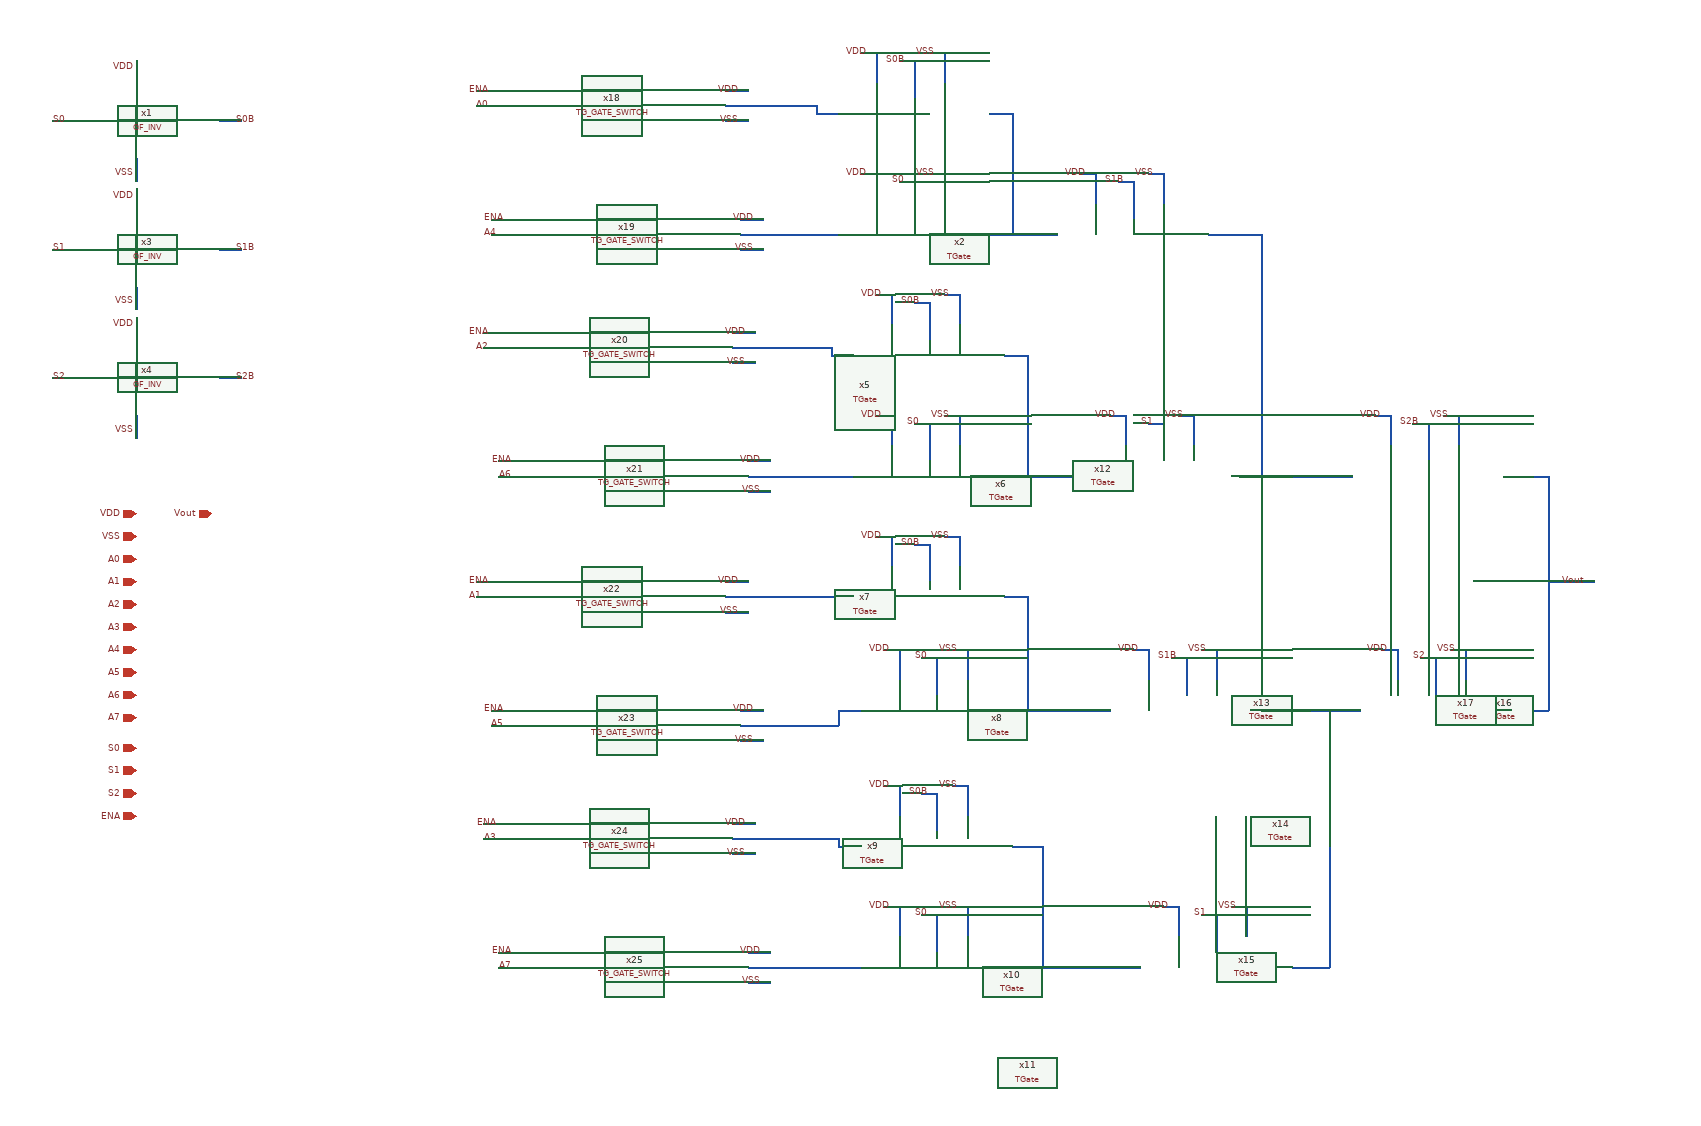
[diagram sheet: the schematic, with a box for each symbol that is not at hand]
v {xschem version=3.4.3 file_version=1.2
}
G {}
K {}
V {}
S {}
E {}
N -660 -160 -660 -130 {
lab=VDD}
N -770 -80 -730 -80 {
lab=S0}
N -660 -30 -660 0 {
lab=VSS}
N -550 -80 -520 -80 {
lab=S0B}
N -660 10 -660 40 {
lab=VDD}
N -770 90 -730 90 {
lab=S1}
N -660 140 -660 170 {
lab=VSS}
N -550 90 -520 90 {
lab=S1B}
N -660 180 -660 210 {
lab=VDD}
N -770 260 -730 260 {
lab=S2}
N -660 310 -660 340 {
lab=VSS}
N -550 260 -520 260 {
lab=S2B}
N 320 -170 320 -130 {
lab=VDD}
N 300 -170 320 -170 {
lab=VDD}
N 370 -160 370 -110 {
lab=S0B}
N 350 -160 370 -160 {
lab=S0B}
N 410 -170 410 -130 {
lab=VSS}
N 390 -170 410 -170 {
lab=VSS}
N 240 -90 270 -90 {
lab=#net1}
N 470 -90 500 -90 {
lab=#net2}
N 320 -10 320 30 {
lab=VDD}
N 300 -10 320 -10 {
lab=VDD}
N 370 0 370 50 {
lab=S0}
N 350 0 370 0 {
lab=S0}
N 410 -10 410 30 {
lab=VSS}
N 390 -10 410 -10 {
lab=VSS}
N 240 70 270 70 {
lab=#net3}
N 340 150 340 190 {
lab=VDD}
N 320 150 340 150 {
lab=VDD}
N 390 160 390 210 {
lab=S0B}
N 370 160 390 160 {
lab=S0B}
N 430 150 430 190 {
lab=VSS}
N 410 150 430 150 {
lab=VSS}
N 260 230 290 230 {
lab=#net4}
N 490 230 520 230 {
lab=#net5}
N 340 310 340 350 {
lab=VDD}
N 320 310 340 310 {
lab=VDD}
N 390 320 390 370 {
lab=S0}
N 370 320 390 320 {
lab=S0}
N 430 310 430 350 {
lab=VSS}
N 410 310 430 310 {
lab=VSS}
N 260 390 290 390 {
lab=#net6}
N 340 470 340 510 {
lab=VDD}
N 320 470 340 470 {
lab=VDD}
N 390 480 390 530 {
lab=S0B}
N 370 480 390 480 {
lab=S0B}
N 430 470 430 510 {
lab=VSS}
N 410 470 430 470 {
lab=VSS}
N 260 550 290 550 {
lab=#net7}
N 490 550 520 550 {
lab=#net8}
N 350 620 350 660 {
lab=VDD}
N 330 620 350 620 {
lab=VDD}
N 400 630 400 680 {
lab=S0}
N 380 630 400 630 {
lab=S0}
N 440 620 440 660 {
lab=VSS}
N 420 620 440 620 {
lab=VSS}
N 270 700 300 700 {
lab=#net9}
N 350 800 350 840 {
lab=VDD}
N 330 800 350 800 {
lab=VDD}
N 400 810 400 860 {
lab=S0B}
N 380 810 400 810 {
lab=S0B}
N 440 800 440 840 {
lab=VSS}
N 420 800 440 800 {
lab=VSS}
N 270 880 300 880 {
lab=#net10}
N 500 880 530 880 {
lab=#net11}
N 350 960 350 1000 {
lab=VDD}
N 330 960 350 960 {
lab=VDD}
N 400 970 400 1020 {
lab=S0}
N 380 970 400 970 {
lab=S0}
N 440 960 440 1000 {
lab=VSS}
N 420 960 440 960 {
lab=VSS}
N 270 1040 300 1040 {
lab=A7}
N 610 -10 610 30 {
lab=VDD}
N 590 -10 610 -10 {
lab=VDD}
N 660 0 660 50 {
lab=S1B}
N 640 0 660 0 {
lab=S1B}
N 700 -10 700 30 {
lab=VSS}
N 680 -10 700 -10 {
lab=VSS}
N 650 310 650 350 {
lab=VDD}
N 630 310 650 310 {
lab=VDD}
N 700 320 700 370 {
lab=S1}
N 680 320 700 320 {
lab=S1}
N 740 310 740 350 {
lab=VSS}
N 720 310 740 310 {
lab=VSS}
N 680 620 680 660 {
lab=VDD}
N 660 620 680 620 {
lab=VDD}
N 730 630 730 680 {
lab=S1B}
N 710 630 730 630 {
lab=S1B}
N 770 620 770 660 {
lab=VSS}
N 750 620 770 620 {
lab=VSS}
N 720 960 720 1000 {
lab=VDD}
N 700 960 720 960 {
lab=VDD}
N 770 970 770 1020 {
lab=S1}
N 750 970 770 970 {
lab=S1}
N 810 960 810 1000 {
lab=VSS}
N 790 960 810 960 {
lab=VSS}
N 870 1040 900 1040 {
lab=#net12}
N 1000 310 1000 350 {
lab=VDD}
N 980 310 1000 310 {
lab=VDD}
N 1050 320 1050 370 {
lab=S2B}
N 1030 320 1050 320 {
lab=S2B}
N 1090 310 1090 350 {
lab=VSS}
N 1070 310 1090 310 {
lab=VSS}
N 1010 620 1010 660 {
lab=VDD}
N 990 620 1010 620 {
lab=VDD}
N 1060 630 1060 680 {
lab=S2}
N 1040 630 1060 630 {
lab=S2}
N 1100 620 1100 660 {
lab=VSS}
N 1080 620 1100 620 {
lab=VSS}
N 470 70 560 70 {
lab=#net2}
N 500 -90 500 70 {
lab=#net2}
N 490 390 600 390 {
lab=#net5}
N 520 230 520 390 {
lab=#net5}
N 500 700 630 700 {
lab=#net8}
N 520 550 520 700 {
lab=#net8}
N 500 1040 670 1040 {
lab=#net11}
N 530 880 540 880 {
lab=#net11}
N 540 880 540 1040 {
lab=#net11}
N 800 390 950 390 {
lab=#net13}
N 830 700 960 700 {
lab=#net12}
N 760 70 830 70 {
lab=#net13}
N 830 70 830 390 {
lab=#net13}
N 900 1040 920 1040 {
lab=#net12}
N 920 700 920 1040 {
lab=#net12}
N 1160 700 1210 700 {
lab=Vout}
N 1210 390 1210 700 {
lab=Vout}
N 1150 390 1210 390 {
lab=Vout}
N 1210 530 1270 530 {
lab=Vout}
N 120 -120 150 -120 {
lab=VDD}
N 120 -100 150 -100 {
lab=#net1}
N 120 -80 150 -80 {
lab=VSS}
N -210 -120 -180 -120 {
lab=ENA}
N -190 -100 -180 -100 {
lab=A0}
N -210 -100 -190 -100 {
lab=A0}
N 140 50 170 50 {
lab=VDD}
N 140 70 170 70 {
lab=#net3}
N 140 90 170 90 {
lab=VSS}
N -190 50 -160 50 {
lab=ENA}
N -170 70 -160 70 {
lab=A4}
N -190 70 -170 70 {
lab=A4}
N 130 200 160 200 {
lab=VDD}
N 130 220 160 220 {
lab=#net4}
N 130 240 160 240 {
lab=VSS}
N -200 200 -170 200 {
lab=ENA}
N -180 220 -170 220 {
lab=A2}
N -200 220 -180 220 {
lab=A2}
N 150 370 180 370 {
lab=VDD}
N 150 390 180 390 {
lab=#net6}
N 150 410 180 410 {
lab=VSS}
N -180 370 -150 370 {
lab=ENA}
N -160 390 -150 390 {
lab=A6}
N -180 390 -160 390 {
lab=A6}
N 120 530 150 530 {
lab=VDD}
N 120 550 150 550 {
lab=#net7}
N 120 570 150 570 {
lab=VSS}
N -210 530 -180 530 {
lab=ENA}
N -190 550 -180 550 {
lab=A1}
N -210 550 -190 550 {
lab=A1}
N 140 700 170 700 {
lab=VDD}
N 140 720 170 720 {
lab=#net9}
N 140 740 170 740 {
lab=VSS}
N -190 700 -160 700 {
lab=ENA}
N -170 720 -160 720 {
lab=A5}
N -190 720 -170 720 {
lab=A5}
N 130 850 160 850 {
lab=VDD}
N 130 870 160 870 {
lab=#net14}
N 130 890 160 890 {
lab=VSS}
N -200 850 -170 850 {
lab=ENA}
N -180 870 -170 870 {
lab=A3}
N -200 870 -180 870 {
lab=A3}
N 150 1020 180 1020 {
lab=VDD}
N 150 1040 180 1040 {
lab=#net15}
N 150 1060 180 1060 {
lab=VSS}
N -180 1020 -150 1020 {
lab=ENA}
N -160 1040 -150 1040 {
lab=#net16}
N -180 1040 -160 1040 {
lab=#net16}
N 150 -100 240 -100 {
lab=#net1}
N 240 -100 240 -90 {
lab=#net1}
N 170 70 240 70 {
lab=#net3}
N 160 220 260 220 {
lab=#net4}
N 260 220 260 230 {
lab=#net4}
N 180 390 260 390 {
lab=#net6}
N 150 550 200 550 {
lab=#net7}
N 200 550 260 550 {
lab=#net7}
N 170 720 270 720 {
lab=#net9}
N 270 700 270 720 {
lab=#net9}
N 160 870 270 870 {}
N 270 870 270 880 {}
N 180 1040 270 1040 {}
C {GF_INV.sym} -660 -80 0 0 {name=x1}
C {devices/lab_wire.sym} -660 -150 0 0 {name=p4 sig_type=std_logic lab=VDD}
C {devices/lab_wire.sym} -750 -80 0 0 {name=p5 sig_type=std_logic lab=S0}
C {devices/lab_wire.sym} -660 -10 0 0 {name=p6 sig_type=std_logic lab=VSS}
C {devices/lab_wire.sym} -530 -80 0 1 {name=p7 sig_type=std_logic lab=S0B}
C {GF_INV.sym} -660 90 0 0 {name=x3}
C {devices/lab_wire.sym} -660 20 0 0 {name=p8 sig_type=std_logic lab=VDD}
C {devices/lab_wire.sym} -750 90 0 0 {name=p9 sig_type=std_logic lab=S1}
C {devices/lab_wire.sym} -660 160 0 0 {name=p10 sig_type=std_logic lab=VSS}
C {devices/lab_wire.sym} -530 90 0 1 {name=p11 sig_type=std_logic lab=S1B}
C {GF_INV.sym} -660 260 0 0 {name=x4}
C {devices/lab_wire.sym} -660 190 0 0 {name=p12 sig_type=std_logic lab=VDD}
C {devices/lab_wire.sym} -750 260 0 0 {name=p13 sig_type=std_logic lab=S2}
C {devices/lab_wire.sym} -660 330 0 0 {name=p14 sig_type=std_logic lab=VSS}
C {devices/lab_wire.sym} -530 260 0 1 {name=p15 sig_type=std_logic lab=S2B}
C {TGate.sym} 490 50 0 0 {name=x2}
C {devices/lab_wire.sym} 310 -170 0 0 {name=p1 sig_type=std_logic lab=VDD}
C {devices/lab_wire.sym} 400 -170 0 0 {name=p2 sig_type=std_logic lab=VSS}
C {TGate.sym} 490 210 0 0 {name=x5}
C {devices/lab_wire.sym} 310 -10 0 0 {name=p3 sig_type=std_logic lab=VDD}
C {devices/lab_wire.sym} 400 -10 0 0 {name=p16 sig_type=std_logic lab=VSS}
C {TGate.sym} 510 370 0 0 {name=x6}
C {devices/lab_wire.sym} 330 150 0 0 {name=p17 sig_type=std_logic lab=VDD}
C {devices/lab_wire.sym} 420 150 0 0 {name=p18 sig_type=std_logic lab=VSS}
C {TGate.sym} 510 530 0 0 {name=x7}
C {devices/lab_wire.sym} 330 310 0 0 {name=p19 sig_type=std_logic lab=VDD}
C {devices/lab_wire.sym} 420 310 0 0 {name=p20 sig_type=std_logic lab=VSS}
C {TGate.sym} 510 690 0 0 {name=x8}
C {devices/lab_wire.sym} 330 470 0 0 {name=p21 sig_type=std_logic lab=VDD}
C {devices/lab_wire.sym} 420 470 0 0 {name=p22 sig_type=std_logic lab=VSS}
C {TGate.sym} 520 840 0 0 {name=x9}
C {devices/lab_wire.sym} 340 620 0 0 {name=p23 sig_type=std_logic lab=VDD}
C {devices/lab_wire.sym} 430 620 0 0 {name=p24 sig_type=std_logic lab=VSS}
C {TGate.sym} 520 1020 0 0 {name=x10}
C {devices/lab_wire.sym} 340 800 0 0 {name=p25 sig_type=std_logic lab=VDD}
C {devices/lab_wire.sym} 430 800 0 0 {name=p26 sig_type=std_logic lab=VSS}
C {TGate.sym} 520 1180 0 0 {name=x11}
C {devices/lab_wire.sym} 340 960 0 0 {name=p27 sig_type=std_logic lab=VDD}
C {devices/lab_wire.sym} 430 960 0 0 {name=p28 sig_type=std_logic lab=VSS}
C {TGate.sym} 780 210 0 0 {name=x12}
C {devices/lab_wire.sym} 600 -10 0 0 {name=p29 sig_type=std_logic lab=VDD}
C {devices/lab_wire.sym} 690 -10 0 0 {name=p30 sig_type=std_logic lab=VSS}
C {TGate.sym} 820 530 0 0 {name=x13}
C {devices/lab_wire.sym} 640 310 0 0 {name=p31 sig_type=std_logic lab=VDD}
C {devices/lab_wire.sym} 730 310 0 0 {name=p32 sig_type=std_logic lab=VSS}
C {TGate.sym} 850 840 0 0 {name=x14}
C {devices/lab_wire.sym} 670 620 0 0 {name=p33 sig_type=std_logic lab=VDD}
C {devices/lab_wire.sym} 760 620 0 0 {name=p34 sig_type=std_logic lab=VSS}
C {TGate.sym} 890 1180 0 0 {name=x15}
C {devices/lab_wire.sym} 710 960 0 0 {name=p35 sig_type=std_logic lab=VDD}
C {devices/lab_wire.sym} 800 960 0 0 {name=p36 sig_type=std_logic lab=VSS}
C {TGate.sym} 1170 530 0 0 {name=x16}
C {devices/lab_wire.sym} 990 310 0 0 {name=p37 sig_type=std_logic lab=VDD}
C {devices/lab_wire.sym} 1080 310 0 0 {name=p38 sig_type=std_logic lab=VSS}
C {TGate.sym} 1180 840 0 0 {name=x17}
C {devices/lab_wire.sym} 1000 620 0 0 {name=p39 sig_type=std_logic lab=VDD}
C {devices/lab_wire.sym} 1090 620 0 0 {name=p40 sig_type=std_logic lab=VSS}
C {devices/lab_wire.sym} 390 970 0 0 {name=p41 sig_type=std_logic lab=S0}
C {devices/lab_wire.sym} 390 810 0 0 {name=p42 sig_type=std_logic lab=S0B}
C {devices/lab_wire.sym} 390 630 0 0 {name=p43 sig_type=std_logic lab=S0}
C {devices/lab_wire.sym} 380 480 0 0 {name=p44 sig_type=std_logic lab=S0B}
C {devices/lab_wire.sym} 380 320 0 0 {name=p45 sig_type=std_logic lab=S0}
C {devices/lab_wire.sym} 380 160 0 0 {name=p46 sig_type=std_logic lab=S0B}
C {devices/lab_wire.sym} 360 0 0 0 {name=p47 sig_type=std_logic lab=S0}
C {devices/lab_wire.sym} 360 -160 0 0 {name=p48 sig_type=std_logic lab=S0B}
C {devices/lab_wire.sym} 650 0 0 0 {name=p49 sig_type=std_logic lab=S1B}
C {devices/lab_wire.sym} 690 320 0 0 {name=p50 sig_type=std_logic lab=S1}
C {devices/lab_wire.sym} 720 630 0 0 {name=p51 sig_type=std_logic lab=S1B}
C {devices/lab_wire.sym} 760 970 0 0 {name=p52 sig_type=std_logic lab=S1}
C {devices/lab_wire.sym} 1050 630 0 0 {name=p53 sig_type=std_logic lab=S2}
C {devices/lab_wire.sym} 1040 320 0 0 {name=p54 sig_type=std_logic lab=S2B}
C {devices/iopin.sym} -660 440 2 0 {name=p55 lab=VDD}
C {devices/iopin.sym} -660 470 2 0 {name=p56 lab=VSS}
C {devices/iopin.sym} -660 500 2 0 {name=p57 lab=A0}
C {devices/iopin.sym} -660 530 2 0 {name=p58 lab=A1}
C {devices/iopin.sym} -660 560 2 0 {name=p59 lab=A2}
C {devices/iopin.sym} -660 590 2 0 {name=p60 lab=A3}
C {devices/iopin.sym} -660 620 2 0 {name=p61 lab=A4}
C {devices/iopin.sym} -660 650 2 0 {name=p62 lab=A5}
C {devices/iopin.sym} -660 680 2 0 {name=p63 lab=A6}
C {devices/iopin.sym} -660 710 2 0 {name=p64 lab=A7}
C {devices/ipin.sym} -660 750 0 0 {name=p65 lab=S0}
C {devices/ipin.sym} -660 780 0 0 {name=p66 lab=S1}
C {devices/ipin.sym} -660 810 0 0 {name=p67 lab=S2}
C {devices/iopin.sym} -560 440 2 0 {name=p68 lab=Vout}
C {devices/lab_wire.sym} -190 -100 0 0 {name=p69 sig_type=std_logic lab=A0}
C {devices/lab_wire.sym} -180 70 0 0 {name=p70 sig_type=std_logic lab=A4}
C {devices/lab_wire.sym} -190 220 0 0 {name=p71 sig_type=std_logic lab=A2}
C {devices/lab_wire.sym} -160 390 0 0 {name=p72 sig_type=std_logic lab=A6}
C {devices/lab_wire.sym} -200 550 0 0 {name=p73 sig_type=std_logic lab=A1}
C {devices/lab_wire.sym} -170 720 0 0 {name=p74 sig_type=std_logic lab=A5}
C {devices/lab_wire.sym} -180 870 0 0 {name=p75 sig_type=std_logic lab=A3}
C {devices/lab_wire.sym} -160 1040 0 0 {name=p76 sig_type=std_logic lab=A7}
C {devices/lab_wire.sym} 1260 530 0 0 {name=p77 sig_type=std_logic lab=Vout}
C {TG_GATE_SWITCH.sym} -30 -100 0 0 {name=x18}
C {TG_GATE_SWITCH.sym} -10 70 0 0 {name=x19}
C {TG_GATE_SWITCH.sym} -20 220 0 0 {name=x20}
C {TG_GATE_SWITCH.sym} 0 390 0 0 {name=x21}
C {TG_GATE_SWITCH.sym} -30 550 0 0 {name=x22}
C {TG_GATE_SWITCH.sym} -10 720 0 0 {name=x23}
C {TG_GATE_SWITCH.sym} -20 870 0 0 {name=x24}
C {TG_GATE_SWITCH.sym} 0 1040 0 0 {name=x25}
C {devices/lab_wire.sym} 140 -120 0 0 {name=p85 sig_type=std_logic lab=VDD}
C {devices/lab_wire.sym} 140 -80 0 0 {name=p86 sig_type=std_logic lab=VSS}
C {devices/ipin.sym} -660 840 0 0 {name=p87 lab=ENA}
C {devices/lab_wire.sym} -160 370 0 0 {name=p88 sig_type=std_logic lab=ENA}
C {devices/lab_wire.sym} -190 200 0 0 {name=p89 sig_type=std_logic lab=ENA}
C {devices/lab_wire.sym} -170 50 0 0 {name=p90 sig_type=std_logic lab=ENA}
C {devices/lab_wire.sym} -190 -120 0 0 {name=p91 sig_type=std_logic lab=ENA}
C {devices/lab_wire.sym} 160 50 0 0 {name=p92 sig_type=std_logic lab=VDD}
C {devices/lab_wire.sym} 160 90 0 0 {name=p93 sig_type=std_logic lab=VSS}
C {devices/lab_wire.sym} 150 200 0 0 {name=p78 sig_type=std_logic lab=VDD}
C {devices/lab_wire.sym} 150 240 0 0 {name=p79 sig_type=std_logic lab=VSS}
C {devices/lab_wire.sym} 170 370 0 0 {name=p80 sig_type=std_logic lab=VDD}
C {devices/lab_wire.sym} 170 410 0 0 {name=p94 sig_type=std_logic lab=VSS}
C {devices/lab_wire.sym} -190 530 0 0 {name=p81 sig_type=std_logic lab=ENA}
C {devices/lab_wire.sym} 140 530 0 0 {name=p95 sig_type=std_logic lab=VDD}
C {devices/lab_wire.sym} 140 570 0 0 {name=p96 sig_type=std_logic lab=VSS}
C {devices/lab_wire.sym} -170 700 0 0 {name=p82 sig_type=std_logic lab=ENA}
C {devices/lab_wire.sym} -180 850 0 0 {name=p97 sig_type=std_logic lab=ENA}
C {devices/lab_wire.sym} -160 1020 0 0 {name=p98 sig_type=std_logic lab=ENA}
C {devices/lab_wire.sym} 160 700 0 0 {name=p99 sig_type=std_logic lab=VDD}
C {devices/lab_wire.sym} 150 850 0 0 {name=p100 sig_type=std_logic lab=VDD}
C {devices/lab_wire.sym} 170 1020 0 0 {name=p101 sig_type=std_logic lab=VDD}
C {devices/lab_wire.sym} 160 740 0 0 {name=p102 sig_type=std_logic lab=VSS}
C {devices/lab_wire.sym} 150 890 0 0 {name=p103 sig_type=std_logic lab=VSS}
C {devices/lab_wire.sym} 170 1060 0 0 {name=p104 sig_type=std_logic lab=VSS}
